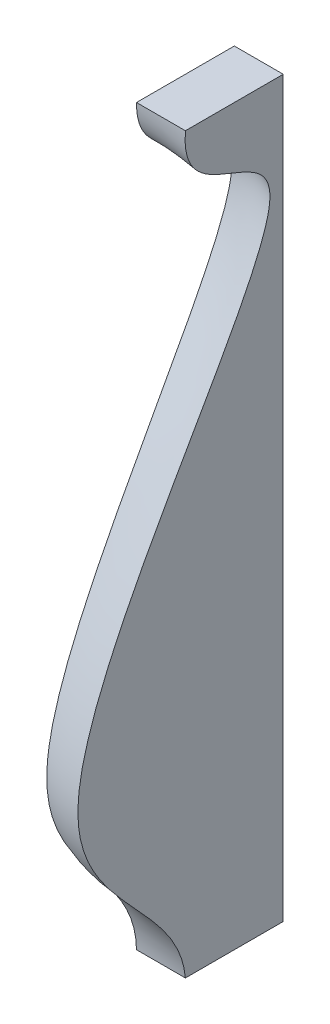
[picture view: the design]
ISO-10303-21;
HEADER;
FILE_DESCRIPTION(('STEP AP214'),'2;1');
FILE_NAME('part.step','',(''),(''),'','','');
FILE_SCHEMA(('AUTOMOTIVE_DESIGN { 1 0 10303 214 1 1 1 1 }'));
ENDSEC;
DATA;
#1=APPLICATION_CONTEXT('core data for automotive mechanical design processes');
#2=APPLICATION_PROTOCOL_DEFINITION('international standard','automotive_design',2000,#1);
#3=PRODUCT_CONTEXT('',#1,'mechanical');
#4=PRODUCT('Part','Part','',(#3));
#5=PRODUCT_RELATED_PRODUCT_CATEGORY('part','',(#4));
#6=PRODUCT_DEFINITION_FORMATION('','',#4);
#7=PRODUCT_DEFINITION_CONTEXT('part definition',#1,'design');
#8=PRODUCT_DEFINITION('design','',#6,#7);
#9=PRODUCT_DEFINITION_SHAPE('','',#8);
#10=(LENGTH_UNIT() NAMED_UNIT(*) SI_UNIT(.MILLI.,.METRE.));
#11=(NAMED_UNIT(*) PLANE_ANGLE_UNIT() SI_UNIT($,.RADIAN.));
#12=(NAMED_UNIT(*) SI_UNIT($,.STERADIAN.) SOLID_ANGLE_UNIT());
#13=UNCERTAINTY_MEASURE_WITH_UNIT(LENGTH_MEASURE(1.E-05),#10,'distance_accuracy_value','');
#14=(GEOMETRIC_REPRESENTATION_CONTEXT(3) GLOBAL_UNCERTAINTY_ASSIGNED_CONTEXT((#13)) GLOBAL_UNIT_ASSIGNED_CONTEXT((#10,
#11,#12)) REPRESENTATION_CONTEXT('',''));
#15=CARTESIAN_POINT('',(0.,0.,0.));
#16=DIRECTION('',(0.,0.,1.));
#17=DIRECTION('',(1.,0.,0.));
#18=AXIS2_PLACEMENT_3D('',#15,#16,#17);
#19=CARTESIAN_POINT('',(-150.,375.,253.120113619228));
#20=DIRECTION('',(1.,0.,0.));
#21=DIRECTION('',(0.,0.,-1.));
#22=AXIS2_PLACEMENT_3D('',#19,#20,#21);
#23=PLANE('',#22);
#24=CARTESIAN_POINT('',(-150.,375.,100.));
#25=CARTESIAN_POINT('',(-150.,374.21653675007,100.066588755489));
#26=CARTESIAN_POINT('',(-150.,373.432207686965,100.123521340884));
#27=CARTESIAN_POINT('',(-150.,371.859019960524,100.216681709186));
#28=CARTESIAN_POINT('',(-150.,371.070156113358,100.252821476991));
#29=CARTESIAN_POINT('',(-150.,369.489544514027,100.302484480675));
#30=CARTESIAN_POINT('',(-150.,368.697794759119,100.315945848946));
#31=CARTESIAN_POINT('',(-150.,367.113088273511,100.318286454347));
#32=CARTESIAN_POINT('',(-150.,366.320131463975,100.307129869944));
#33=CARTESIAN_POINT('',(-150.,364.734681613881,100.25826156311));
#34=CARTESIAN_POINT('',(-150.,363.942188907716,100.220538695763));
#35=CARTESIAN_POINT('',(-150.,362.348389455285,100.115833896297));
#36=CARTESIAN_POINT('',(-150.,361.54710777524,100.048464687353));
#37=CARTESIAN_POINT('',(-150.,359.94848717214,99.8823244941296));
#38=CARTESIAN_POINT('',(-150.,359.151145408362,99.7835810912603));
#39=CARTESIAN_POINT('',(-150.,357.56214923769,99.5526394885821));
#40=CARTESIAN_POINT('',(-150.,356.770489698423,99.420476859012));
#41=CARTESIAN_POINT('',(-150.,355.194608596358,99.1206798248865));
#42=CARTESIAN_POINT('',(-150.,354.410381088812,98.9530768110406));
#43=CARTESIAN_POINT('',(-150.,352.851074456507,98.5804242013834));
#44=CARTESIAN_POINT('',(-150.,352.075992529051,98.3753864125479));
#45=CARTESIAN_POINT('',(-150.,350.724720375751,97.9808842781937));
#46=CARTESIAN_POINT('',(-150.,350.146075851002,97.7997941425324));
#47=CARTESIAN_POINT('',(-150.,348.996367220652,97.4145841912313));
#48=CARTESIAN_POINT('',(-150.,348.425304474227,97.2104603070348));
#49=CARTESIAN_POINT('',(-150.,347.292094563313,96.7787729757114));
#50=CARTESIAN_POINT('',(-150.,346.729947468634,96.5512093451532));
#51=CARTESIAN_POINT('',(-150.,345.61582654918,96.0723947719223));
#52=CARTESIAN_POINT('',(-150.,345.063852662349,95.8211439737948));
#53=CARTESIAN_POINT('',(-150.,343.974984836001,95.2966788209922));
#54=CARTESIAN_POINT('',(-150.,343.438014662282,95.0236228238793));
#55=CARTESIAN_POINT('',(-150.,342.376502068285,94.4542750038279));
#56=CARTESIAN_POINT('',(-150.,341.851960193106,94.1579821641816));
#57=CARTESIAN_POINT('',(-150.,340.816444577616,93.542594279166));
#58=CARTESIAN_POINT('',(-150.,340.30547047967,93.2234998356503));
#59=CARTESIAN_POINT('',(-150.,339.29809746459,92.5631666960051));
#60=CARTESIAN_POINT('',(-150.,338.801697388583,92.2219297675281));
#61=CARTESIAN_POINT('',(-150.,337.824157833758,91.5180631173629));
#62=CARTESIAN_POINT('',(-150.,337.343021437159,91.1554291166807));
#63=CARTESIAN_POINT('',(-150.,336.396709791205,90.4098173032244));
#64=CARTESIAN_POINT('',(-150.,335.931536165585,90.0268374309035));
#65=CARTESIAN_POINT('',(-150.,335.017676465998,89.2417622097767));
#66=CARTESIAN_POINT('',(-150.,334.568989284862,88.8396681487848));
#67=CARTESIAN_POINT('',(-150.,333.688265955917,88.0175748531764));
#68=CARTESIAN_POINT('',(-150.,333.25623143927,87.5975738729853));
#69=CARTESIAN_POINT('',(-150.,332.407491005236,86.7396163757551));
#70=CARTESIAN_POINT('',(-150.,331.990840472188,86.3016050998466));
#71=CARTESIAN_POINT('',(-150.,331.174201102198,85.4102924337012));
#72=CARTESIAN_POINT('',(-150.,330.774213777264,84.9569896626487));
#73=CARTESIAN_POINT('',(-150.,329.598888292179,83.576292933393));
#74=CARTESIAN_POINT('',(-150.,328.848012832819,82.6279335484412));
#75=CARTESIAN_POINT('',(-150.,327.467283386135,80.7666367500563));
#76=CARTESIAN_POINT('',(-150.,326.832556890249,79.8572749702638));
#77=CARTESIAN_POINT('',(-150.,325.610003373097,78.0077037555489));
#78=CARTESIAN_POINT('',(-150.,325.022174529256,77.0674955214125));
#79=CARTESIAN_POINT('',(-150.,323.889712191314,75.1649302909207));
#80=CARTESIAN_POINT('',(-150.,323.34496828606,74.2026386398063));
#81=CARTESIAN_POINT('',(-150.,322.291476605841,72.2586952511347));
#82=CARTESIAN_POINT('',(-150.,321.782727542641,71.2770442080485));
#83=CARTESIAN_POINT('',(-150.,320.63552275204,68.9777823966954));
#84=CARTESIAN_POINT('',(-150.,320.008519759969,67.6544774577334));
#85=CARTESIAN_POINT('',(-150.,318.794868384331,64.9892511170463));
#86=CARTESIAN_POINT('',(-150.,318.208231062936,63.6473247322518));
#87=CARTESIAN_POINT('',(-150.,317.062805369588,60.9513675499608));
#88=CARTESIAN_POINT('',(-150.,316.504023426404,59.597334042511));
#89=CARTESIAN_POINT('',(-150.,315.397407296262,56.8714769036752));
#90=CARTESIAN_POINT('',(-150.,314.849706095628,55.4995997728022));
#91=CARTESIAN_POINT('',(-150.,313.757540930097,52.7549957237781));
#92=CARTESIAN_POINT('',(-150.,313.213076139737,51.3822691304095));
#93=CARTESIAN_POINT('',(-150.,312.114075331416,48.6410881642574));
#94=CARTESIAN_POINT('',(-150.,311.559541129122,47.2726330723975));
#95=CARTESIAN_POINT('',(-150.,310.560688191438,44.8696426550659));
#96=CARTESIAN_POINT('',(-150.,310.121475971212,43.8329980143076));
#97=CARTESIAN_POINT('',(-150.,309.221955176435,41.7687426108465));
#98=CARTESIAN_POINT('',(-150.,308.761644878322,40.7411325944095));
#99=CARTESIAN_POINT('',(-150.,307.812238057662,38.6985133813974));
#100=CARTESIAN_POINT('',(-150.,307.323125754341,37.6835114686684));
#101=CARTESIAN_POINT('',(-150.,306.307310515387,35.6701753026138));
#102=CARTESIAN_POINT('',(-150.,305.780544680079,34.6718725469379));
#103=CARTESIAN_POINT('',(-150.,304.689245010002,32.7148472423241));
#104=CARTESIAN_POINT('',(-150.,304.125369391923,31.7557607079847));
#105=CARTESIAN_POINT('',(-150.,302.94448102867,29.8710201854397));
#106=CARTESIAN_POINT('',(-150.,302.327483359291,28.9453568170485));
#107=CARTESIAN_POINT('',(-150.,301.032771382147,27.1401042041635));
#108=CARTESIAN_POINT('',(-150.,300.355198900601,26.2604146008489));
#109=CARTESIAN_POINT('',(-150.,299.287718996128,24.9849865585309));
#110=CARTESIAN_POINT('',(-150.,298.923665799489,24.5674930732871));
#111=CARTESIAN_POINT('',(-150.,298.177696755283,23.7488161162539));
#112=CARTESIAN_POINT('',(-150.,297.795783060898,23.3476306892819));
#113=CARTESIAN_POINT('',(-150.,296.968191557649,22.5180017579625));
#114=CARTESIAN_POINT('',(-150.,296.52025836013,22.0918005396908));
#115=CARTESIAN_POINT('',(-150.,295.60124663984,21.2648995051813));
#116=CARTESIAN_POINT('',(-150.,295.13016385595,20.864204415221));
#117=CARTESIAN_POINT('',(-150.,294.165268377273,20.0911470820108));
#118=CARTESIAN_POINT('',(-150.,293.671456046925,19.7187843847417));
#119=CARTESIAN_POINT('',(-150.,292.661853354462,19.0047717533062));
#120=CARTESIAN_POINT('',(-150.,292.146056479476,18.6631310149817));
#121=CARTESIAN_POINT('',(-150.,291.094083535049,18.0127470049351));
#122=CARTESIAN_POINT('',(-150.,290.557906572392,17.7040051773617));
#123=CARTESIAN_POINT('',(-150.,289.467181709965,17.120952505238));
#124=CARTESIAN_POINT('',(-150.,288.912635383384,16.8466387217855));
#125=CARTESIAN_POINT('',(-150.,287.928683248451,16.3976627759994));
#126=CARTESIAN_POINT('',(-150.,287.502783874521,16.2152650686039));
#127=CARTESIAN_POINT('',(-150.,286.642984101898,15.8702954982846));
#128=CARTESIAN_POINT('',(-150.,286.209083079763,15.7077251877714));
#129=CARTESIAN_POINT('',(-150.,285.33444189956,15.4023310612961));
#130=CARTESIAN_POINT('',(-150.,284.893702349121,15.2595055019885));
#131=CARTESIAN_POINT('',(-150.,284.006359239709,14.9932546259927));
#132=CARTESIAN_POINT('',(-150.,283.559755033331,14.8698314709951));
#133=CARTESIAN_POINT('',(-150.,282.661325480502,14.6418217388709));
#134=CARTESIAN_POINT('',(-150.,282.209495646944,14.5372528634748));
#135=CARTESIAN_POINT('',(-150.,281.301960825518,14.3464721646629));
#136=CARTESIAN_POINT('',(-150.,280.846255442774,14.2602622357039));
#137=CARTESIAN_POINT('',(-150.,279.474645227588,14.028127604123));
#138=CARTESIAN_POINT('',(-150.,278.554159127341,13.9086762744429));
#139=CARTESIAN_POINT('',(-150.,276.697492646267,13.7330760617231));
#140=CARTESIAN_POINT('',(-150.,275.7612498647,13.6776205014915));
#141=CARTESIAN_POINT('',(-150.,273.886746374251,13.625270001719));
#142=CARTESIAN_POINT('',(-150.,272.948484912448,13.6284031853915));
#143=CARTESIAN_POINT('',(-150.,271.542442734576,13.6720229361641));
#144=CARTESIAN_POINT('',(-150.,271.073942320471,13.6930533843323));
#145=CARTESIAN_POINT('',(-150.,270.13763650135,13.7473078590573));
#146=CARTESIAN_POINT('',(-150.,269.669831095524,13.7805318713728));
#147=CARTESIAN_POINT('',(-150.,268.733577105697,13.8585469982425));
#148=CARTESIAN_POINT('',(-150.,268.265131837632,13.9033774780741));
#149=CARTESIAN_POINT('',(-150.,267.329408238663,14.0038645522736));
#150=CARTESIAN_POINT('',(-150.,266.862129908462,14.0595211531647));
#151=CARTESIAN_POINT('',(-150.,265.929013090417,14.1808012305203));
#152=CARTESIAN_POINT('',(-150.,265.463174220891,14.2464217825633));
#153=CARTESIAN_POINT('',(-150.,264.532883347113,14.3867891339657));
#154=CARTESIAN_POINT('',(-150.,264.06843134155,14.4615359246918));
#155=CARTESIAN_POINT('',(-150.,262.677292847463,14.6983326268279));
#156=CARTESIAN_POINT('',(-150.,261.752728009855,14.8729516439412));
#157=CARTESIAN_POINT('',(-150.,260.000822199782,15.23198624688));
#158=CARTESIAN_POINT('',(-150.,259.172922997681,15.4137178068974));
#159=CARTESIAN_POINT('',(-150.,257.521795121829,15.7974210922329));
#160=CARTESIAN_POINT('',(-150.,256.698566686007,15.9993938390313));
#161=CARTESIAN_POINT('',(-150.,255.056365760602,16.421225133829));
#162=CARTESIAN_POINT('',(-150.,254.237395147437,16.6410909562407));
#163=CARTESIAN_POINT('',(-150.,252.60388138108,17.096608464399));
#164=CARTESIAN_POINT('',(-150.,251.789338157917,17.3322598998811));
#165=CARTESIAN_POINT('',(-150.,250.16346493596,17.8179445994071));
#166=CARTESIAN_POINT('',(-150.,249.352140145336,18.0679952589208));
#167=CARTESIAN_POINT('',(-150.,247.733506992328,18.5807609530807));
#168=CARTESIAN_POINT('',(-150.,246.926198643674,18.8434760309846));
#169=CARTESIAN_POINT('',(-150.,245.314470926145,19.3806316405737));
#170=CARTESIAN_POINT('',(-150.,244.510055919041,19.6550852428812));
#171=CARTESIAN_POINT('',(-150.,242.904837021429,20.2143688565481));
#172=CARTESIAN_POINT('',(-150.,242.104033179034,20.499199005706));
#173=CARTESIAN_POINT('',(-150.,239.705806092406,21.3681600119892));
#174=CARTESIAN_POINT('',(-150.,238.113500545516,21.9664479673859));
#175=CARTESIAN_POINT('',(-150.,234.941514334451,23.1944367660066));
#176=CARTESIAN_POINT('',(-150.,233.36183097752,23.8241306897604));
#177=CARTESIAN_POINT('',(-150.,230.203288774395,25.1144376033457));
#178=CARTESIAN_POINT('',(-150.,228.624500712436,25.7752235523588));
#179=CARTESIAN_POINT('',(-150.,225.478553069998,27.1193081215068));
#180=CARTESIAN_POINT('',(-150.,223.911382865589,27.8025819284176));
#181=CARTESIAN_POINT('',(-150.,220.787111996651,29.1886679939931));
#182=CARTESIAN_POINT('',(-150.,219.230004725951,29.8914653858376));
#183=CARTESIAN_POINT('',(-150.,216.124550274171,31.3141680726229));
#184=CARTESIAN_POINT('',(-150.,214.576199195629,32.034064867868));
#185=CARTESIAN_POINT('',(-150.,212.259309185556,33.1252859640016));
#186=CARTESIAN_POINT('',(-150.,211.488059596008,33.490870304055));
#187=CARTESIAN_POINT('',(-150.,209.947273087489,34.2256351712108));
#188=CARTESIAN_POINT('',(-150.,209.177736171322,34.5948157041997));
#189=CARTESIAN_POINT('',(-150.,207.640376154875,35.3365139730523));
#190=CARTESIAN_POINT('',(-150.,206.872552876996,35.7090313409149));
#191=CARTESIAN_POINT('',(-150.,205.338463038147,36.457242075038));
#192=CARTESIAN_POINT('',(-150.,204.572196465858,36.8329354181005));
#193=CARTESIAN_POINT('',(-150.,201.997162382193,38.1016951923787));
#194=CARTESIAN_POINT('',(-150.,200.191771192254,39.001622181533));
#195=CARTESIAN_POINT('',(-150.,196.588308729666,40.8160282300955));
#196=CARTESIAN_POINT('',(-150.,194.790237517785,41.7305074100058));
#197=CARTESIAN_POINT('',(-150.,191.200524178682,43.5722494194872));
#198=CARTESIAN_POINT('',(-150.,189.408882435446,44.4995129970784));
#199=CARTESIAN_POINT('',(-150.,185.831432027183,46.365206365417));
#200=CARTESIAN_POINT('',(-150.,184.045623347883,47.3036361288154));
#201=CARTESIAN_POINT('',(-150.,180.478979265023,49.1904276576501));
#202=CARTESIAN_POINT('',(-150.,178.698144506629,50.1387906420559));
#203=CARTESIAN_POINT('',(-150.,175.141101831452,52.0441575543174));
#204=CARTESIAN_POINT('',(-150.,173.364893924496,53.0011615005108));
#205=CARTESIAN_POINT('',(-150.,168.042124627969,55.8836989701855));
#206=CARTESIAN_POINT('',(-150.,164.501717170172,57.8205992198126));
#207=CARTESIAN_POINT('',(-150.,157.433752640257,61.7176161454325));
#208=CARTESIAN_POINT('',(-150.,153.90619550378,63.6777327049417));
#209=CARTESIAN_POINT('',(-150.,146.856580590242,67.6178956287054));
#210=CARTESIAN_POINT('',(-150.,143.334534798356,69.5979634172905));
#211=CARTESIAN_POINT('',(-150.,136.297984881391,73.5706523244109));
#212=CARTESIAN_POINT('',(-150.,132.783480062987,75.563272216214));
#213=CARTESIAN_POINT('',(-150.,125.759562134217,79.5569953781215));
#214=CARTESIAN_POINT('',(-150.,122.250148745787,81.5580981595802));
#215=CARTESIAN_POINT('',(-150.,115.234233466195,85.5651869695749));
#216=CARTESIAN_POINT('',(-150.,111.727731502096,87.5711728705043));
#217=CARTESIAN_POINT('',(-150.,104.715655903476,91.5847729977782));
#218=CARTESIAN_POINT('',(-150.,101.210082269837,93.5923872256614));
#219=CARTESIAN_POINT('',(-150.,93.3492371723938,98.0920857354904));
#220=CARTESIAN_POINT('',(-150.,88.9937416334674,100.583778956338));
#221=CARTESIAN_POINT('',(-150.,80.2782170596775,105.55946742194));
#222=CARTESIAN_POINT('',(-150.,75.9181879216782,108.043462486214));
#223=CARTESIAN_POINT('',(-150.,67.1906031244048,112.998412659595));
#224=CARTESIAN_POINT('',(-150.,62.8230473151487,115.469367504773));
#225=CARTESIAN_POINT('',(-150.,54.0774394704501,120.392937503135));
#226=CARTESIAN_POINT('',(-150.,49.6993871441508,122.845552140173));
#227=CARTESIAN_POINT('',(-150.,40.9325384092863,127.725490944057));
#228=CARTESIAN_POINT('',(-150.,36.5437497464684,130.152829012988));
#229=CARTESIAN_POINT('',(-150.,27.7499512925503,134.977900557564));
#230=CARTESIAN_POINT('',(-150.,23.3449416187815,137.375634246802));
#231=CARTESIAN_POINT('',(-150.,14.5157681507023,142.135202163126));
#232=CARTESIAN_POINT('',(-150.,10.09160508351,144.497037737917));
#233=CARTESIAN_POINT('',(-150.,1.2208532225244,149.177958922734));
#234=CARTESIAN_POINT('',(-150.,-3.2257348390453,151.497045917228));
#235=CARTESIAN_POINT('',(-150.,-8.95319422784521,154.443019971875));
#236=CARTESIAN_POINT('',(-150.,-10.2221397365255,155.093132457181));
#237=CARTESIAN_POINT('',(-150.,-12.7622193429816,156.389071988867));
#238=CARTESIAN_POINT('',(-150.,-14.0333534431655,157.034899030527));
#239=CARTESIAN_POINT('',(-150.,-17.8503370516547,158.965736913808));
#240=CARTESIAN_POINT('',(-150.,-20.3995969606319,160.244016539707));
#241=CARTESIAN_POINT('',(-150.,-25.508054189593,162.780943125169));
#242=CARTESIAN_POINT('',(-150.,-28.0672520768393,164.039588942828));
#243=CARTESIAN_POINT('',(-150.,-33.1963438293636,166.535320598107));
#244=CARTESIAN_POINT('',(-150.,-35.7662383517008,167.772405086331));
#245=CARTESIAN_POINT('',(-150.,-40.9175691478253,170.222901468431));
#246=CARTESIAN_POINT('',(-150.,-43.4990063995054,171.436311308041));
#247=CARTESIAN_POINT('',(-150.,-48.6914154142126,173.845031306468));
#248=CARTESIAN_POINT('',(-150.,-51.3024690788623,175.040165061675));
#249=CARTESIAN_POINT('',(-150.,-56.5377935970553,177.401192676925));
#250=CARTESIAN_POINT('',(-150.,-59.1620645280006,178.567086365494));
#251=CARTESIAN_POINT('',(-150.,-64.424522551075,180.866443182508));
#252=CARTESIAN_POINT('',(-150.,-67.0627084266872,181.999909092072));
#253=CARTESIAN_POINT('',(-150.,-72.3538513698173,184.230851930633));
#254=CARTESIAN_POINT('',(-150.,-75.0068063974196,185.328333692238));
#255=CARTESIAN_POINT('',(-150.,-80.3285429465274,187.483311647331));
#256=CARTESIAN_POINT('',(-150.,-82.9973224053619,188.540812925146));
#257=CARTESIAN_POINT('',(-150.,-87.9347409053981,190.44993295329));
#258=CARTESIAN_POINT('',(-150.,-90.2009055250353,191.307948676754));
#259=CARTESIAN_POINT('',(-150.,-94.7461611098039,192.989041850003));
#260=CARTESIAN_POINT('',(-150.,-97.0252519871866,193.81211953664));
#261=CARTESIAN_POINT('',(-150.,-101.597317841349,195.419762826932));
#262=CARTESIAN_POINT('',(-150.,-103.890294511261,196.204323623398));
#263=CARTESIAN_POINT('',(-150.,-108.491268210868,197.730841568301));
#264=CARTESIAN_POINT('',(-150.,-110.799270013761,198.472784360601));
#265=CARTESIAN_POINT('',(-150.,-115.431641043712,199.90933696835));
#266=CARTESIAN_POINT('',(-150.,-117.756019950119,200.603915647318));
#267=CARTESIAN_POINT('',(-150.,-122.422768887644,201.940218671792));
#268=CARTESIAN_POINT('',(-150.,-124.765156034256,202.581883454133));
#269=CARTESIAN_POINT('',(-150.,-129.442344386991,203.798660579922));
#270=CARTESIAN_POINT('',(-150.,-131.776989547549,204.374371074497));
#271=CARTESIAN_POINT('',(-150.,-136.462638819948,205.458979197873));
#272=CARTESIAN_POINT('',(-150.,-138.813647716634,205.967856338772));
#273=CARTESIAN_POINT('',(-150.,-142.350836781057,206.673832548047));
#274=CARTESIAN_POINT('',(-150.,-143.531346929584,206.899546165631));
#275=CARTESIAN_POINT('',(-150.,-145.896096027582,207.330611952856));
#276=CARTESIAN_POINT('',(-150.,-147.080334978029,207.535964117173));
#277=CARTESIAN_POINT('',(-150.,-149.451071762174,207.924670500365));
#278=CARTESIAN_POINT('',(-150.,-150.63756561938,208.108048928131));
#279=CARTESIAN_POINT('',(-150.,-153.013915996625,208.451520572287));
#280=CARTESIAN_POINT('',(-150.,-154.203772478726,208.61161405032));
#281=CARTESIAN_POINT('',(-150.,-156.585258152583,208.906662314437));
#282=CARTESIAN_POINT('',(-150.,-157.776883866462,209.041645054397));
#283=CARTESIAN_POINT('',(-150.,-160.162880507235,209.284848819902));
#284=CARTESIAN_POINT('',(-150.,-161.357251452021,209.393069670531));
#285=CARTESIAN_POINT('',(-150.,-163.747850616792,209.580721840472));
#286=CARTESIAN_POINT('',(-150.,-164.944078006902,209.660163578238));
#287=CARTESIAN_POINT('',(-150.,-166.739622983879,209.756095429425));
#288=CARTESIAN_POINT('',(-150.,-167.338335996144,209.784200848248));
#289=CARTESIAN_POINT('',(-150.,-168.536080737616,209.832471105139));
#290=CARTESIAN_POINT('',(-150.,-169.135112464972,209.852635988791));
#291=CARTESIAN_POINT('',(-150.,-170.49711131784,209.889329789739));
#292=CARTESIAN_POINT('',(-150.,-171.260147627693,209.903359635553));
#293=CARTESIAN_POINT('',(-150.,-172.786330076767,209.918128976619));
#294=CARTESIAN_POINT('',(-150.,-173.54947621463,209.91886862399));
#295=CARTESIAN_POINT('',(-150.,-175.8391890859,209.900805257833));
#296=CARTESIAN_POINT('',(-150.,-177.365653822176,209.861709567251));
#297=CARTESIAN_POINT('',(-150.,-180.416226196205,209.727784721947));
#298=CARTESIAN_POINT('',(-150.,-181.940333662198,209.632951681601));
#299=CARTESIAN_POINT('',(-150.,-184.983915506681,209.386261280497));
#300=CARTESIAN_POINT('',(-150.,-186.503389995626,209.234405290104));
#301=CARTESIAN_POINT('',(-150.,-189.535394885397,208.872761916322));
#302=CARTESIAN_POINT('',(-150.,-191.047925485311,208.662976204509));
#303=CARTESIAN_POINT('',(-150.,-194.061898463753,208.185283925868));
#304=CARTESIAN_POINT('',(-150.,-195.563352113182,207.917448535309));
#305=CARTESIAN_POINT('',(-150.,-198.554832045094,207.32347300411));
#306=CARTESIAN_POINT('',(-150.,-200.044857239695,206.997327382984));
#307=CARTESIAN_POINT('',(-150.,-203.011110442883,206.287224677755));
#308=CARTESIAN_POINT('',(-150.,-204.487338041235,205.903265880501));
#309=CARTESIAN_POINT('',(-150.,-207.423765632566,205.078539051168));
#310=CARTESIAN_POINT('',(-150.,-208.883966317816,204.637773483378));
#311=CARTESIAN_POINT('',(-150.,-211.786218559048,203.700967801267));
#312=CARTESIAN_POINT('',(-150.,-213.228273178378,203.204937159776));
#313=CARTESIAN_POINT('',(-150.,-216.438013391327,202.033428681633));
#314=CARTESIAN_POINT('',(-150.,-218.200442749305,201.343510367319));
#315=CARTESIAN_POINT('',(-150.,-221.692689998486,199.88575453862));
#316=CARTESIAN_POINT('',(-150.,-223.422507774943,199.117916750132));
#317=CARTESIAN_POINT('',(-150.,-226.848126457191,197.509339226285));
#318=CARTESIAN_POINT('',(-150.,-228.543922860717,196.668589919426));
#319=CARTESIAN_POINT('',(-150.,-231.900382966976,194.91992859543));
#320=CARTESIAN_POINT('',(-150.,-233.561047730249,194.012018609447));
#321=CARTESIAN_POINT('',(-150.,-236.852124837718,192.132166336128));
#322=CARTESIAN_POINT('',(-150.,-238.48243405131,191.160043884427));
#323=CARTESIAN_POINT('',(-150.,-241.708323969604,189.160358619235));
#324=CARTESIAN_POINT('',(-150.,-243.303909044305,188.132802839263));
#325=CARTESIAN_POINT('',(-150.,-246.461838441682,186.02827140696));
#326=CARTESIAN_POINT('',(-150.,-248.024186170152,184.951300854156));
#327=CARTESIAN_POINT('',(-150.,-251.117230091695,182.754138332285));
#328=CARTESIAN_POINT('',(-150.,-252.647937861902,181.633962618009));
#329=CARTESIAN_POINT('',(-150.,-256.207052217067,178.960329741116));
#330=CARTESIAN_POINT('',(-150.,-258.223836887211,177.391410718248));
#331=CARTESIAN_POINT('',(-150.,-262.212337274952,174.198129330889));
#332=CARTESIAN_POINT('',(-150.,-264.18405922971,172.57377471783));
#333=CARTESIAN_POINT('',(-150.,-268.091832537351,169.280840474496));
#334=CARTESIAN_POINT('',(-150.,-270.027864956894,167.612238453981));
#335=CARTESIAN_POINT('',(-150.,-273.873475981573,164.241911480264));
#336=CARTESIAN_POINT('',(-150.,-275.783032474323,162.540161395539));
#337=CARTESIAN_POINT('',(-150.,-279.584914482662,159.114625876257));
#338=CARTESIAN_POINT('',(-150.,-281.47722534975,157.390824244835));
#339=CARTESIAN_POINT('',(-150.,-285.253952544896,153.932412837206));
#340=CARTESIAN_POINT('',(-150.,-287.138363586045,152.197797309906));
#341=CARTESIAN_POINT('',(-150.,-290.906536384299,148.731418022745));
#342=CARTESIAN_POINT('',(-150.,-292.79029708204,146.999653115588));
#343=CARTESIAN_POINT('',(-150.,-296.568819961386,143.549283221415));
#344=CARTESIAN_POINT('',(-150.,-298.463578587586,141.830674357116));
#345=CARTESIAN_POINT('',(-150.,-302.273923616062,138.419642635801));
#346=CARTESIAN_POINT('',(-150.,-304.189492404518,136.727200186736));
#347=CARTESIAN_POINT('',(-150.,-308.051925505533,133.382245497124));
#348=CARTESIAN_POINT('',(-150.,-309.998755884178,131.729694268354));
#349=CARTESIAN_POINT('',(-150.,-313.934930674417,128.479192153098));
#350=CARTESIAN_POINT('',(-150.,-315.924238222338,126.881196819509));
#351=CARTESIAN_POINT('',(-150.,-319.957681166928,123.755482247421));
#352=CARTESIAN_POINT('',(-150.,-322.001815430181,122.227761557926));
#353=CARTESIAN_POINT('',(-150.,-325.291926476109,119.878375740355));
#354=CARTESIAN_POINT('',(-150.,-326.516731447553,119.027032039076));
#355=CARTESIAN_POINT('',(-150.,-328.990551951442,117.359163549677));
#356=CARTESIAN_POINT('',(-150.,-330.239576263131,116.54265174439));
#357=CARTESIAN_POINT('',(-150.,-332.763008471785,114.949283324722));
#358=CARTESIAN_POINT('',(-150.,-334.037420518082,114.172433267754));
#359=CARTESIAN_POINT('',(-150.,-336.612818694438,112.663207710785));
#360=CARTESIAN_POINT('',(-150.,-337.913811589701,111.930843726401));
#361=CARTESIAN_POINT('',(-150.,-340.536252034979,110.519286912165));
#362=CARTESIAN_POINT('',(-150.,-341.857569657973,109.839853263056));
#363=CARTESIAN_POINT('',(-150.,-344.526809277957,108.535259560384));
#364=CARTESIAN_POINT('',(-150.,-345.87473138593,107.910099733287));
#365=CARTESIAN_POINT('',(-150.,-348.596027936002,106.719206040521));
#366=CARTESIAN_POINT('',(-150.,-349.969392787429,106.153450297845));
#367=CARTESIAN_POINT('',(-150.,-352.740265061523,105.0859307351));
#368=CARTESIAN_POINT('',(-150.,-354.137762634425,104.584141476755));
#369=CARTESIAN_POINT('',(-150.,-356.331575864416,103.855571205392));
#370=CARTESIAN_POINT('',(-150.,-357.120182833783,103.605377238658));
#371=CARTESIAN_POINT('',(-150.,-358.703909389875,103.126693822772));
#372=CARTESIAN_POINT('',(-150.,-359.499028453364,102.898202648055));
#373=CARTESIAN_POINT('',(-150.,-361.095253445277,102.463475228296));
#374=CARTESIAN_POINT('',(-150.,-361.896358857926,102.257237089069));
#375=CARTESIAN_POINT('',(-150.,-363.504028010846,101.867457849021));
#376=CARTESIAN_POINT('',(-150.,-364.310591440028,101.68391546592));
#377=CARTESIAN_POINT('',(-150.,-365.934639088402,101.338596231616));
#378=CARTESIAN_POINT('',(-150.,-366.752159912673,101.176991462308));
#379=CARTESIAN_POINT('',(-150.,-368.391575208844,100.877425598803));
#380=CARTESIAN_POINT('',(-150.,-369.213469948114,100.739465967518));
#381=CARTESIAN_POINT('',(-150.,-370.861035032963,100.487345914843));
#382=CARTESIAN_POINT('',(-150.,-371.686705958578,100.373189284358));
#383=CARTESIAN_POINT('',(-150.,-373.341208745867,100.168702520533));
#384=CARTESIAN_POINT('',(-150.,-374.170041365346,100.078378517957));
#385=CARTESIAN_POINT('',(-150.,-375.,100.));
#386=B_SPLINE_CURVE_WITH_KNOTS('',3,(#24,#25,#26,#27,#28,#29,#30,#31,#32,#33,#34,#35,#36,#37,
#38,#39,#40,#41,#42,#43,#44,#45,#46,#47,#48,#49,#50,#51,#52,#53,#54,#55,#56,#57,#58,#59,#60,#61,
#62,#63,#64,#65,#66,#67,#68,#69,#70,#71,#72,#73,#74,#75,#76,#77,#78,#79,#80,#81,#82,#83,#84,#85,
#86,#87,#88,#89,#90,#91,#92,#93,#94,#95,#96,#97,#98,#99,#100,#101,#102,#103,#104,#105,#106,#107,
#108,#109,#110,#111,#112,#113,#114,#115,#116,#117,#118,#119,#120,#121,#122,#123,#124,#125,#126,
#127,#128,#129,#130,#131,#132,#133,#134,#135,#136,#137,#138,#139,#140,#141,#142,#143,#144,#145,
#146,#147,#148,#149,#150,#151,#152,#153,#154,#155,#156,#157,#158,#159,#160,#161,#162,#163,#164,
#165,#166,#167,#168,#169,#170,#171,#172,#173,#174,#175,#176,#177,#178,#179,#180,#181,#182,#183,
#184,#185,#186,#187,#188,#189,#190,#191,#192,#193,#194,#195,#196,#197,#198,#199,#200,#201,#202,
#203,#204,#205,#206,#207,#208,#209,#210,#211,#212,#213,#214,#215,#216,#217,#218,#219,#220,#221,
#222,#223,#224,#225,#226,#227,#228,#229,#230,#231,#232,#233,#234,#235,#236,#237,#238,#239,#240,
#241,#242,#243,#244,#245,#246,#247,#248,#249,#250,#251,#252,#253,#254,#255,#256,#257,#258,#259,
#260,#261,#262,#263,#264,#265,#266,#267,#268,#269,#270,#271,#272,#273,#274,#275,#276,#277,#278,
#279,#280,#281,#282,#283,#284,#285,#286,#287,#288,#289,#290,#291,#292,#293,#294,#295,#296,#297,
#298,#299,#300,#301,#302,#303,#304,#305,#306,#307,#308,#309,#310,#311,#312,#313,#314,#315,#316,
#317,#318,#319,#320,#321,#322,#323,#324,#325,#326,#327,#328,#329,#330,#331,#332,#333,#334,#335,
#336,#337,#338,#339,#340,#341,#342,#343,#344,#345,#346,#347,#348,#349,#350,#351,#352,#353,#354,
#355,#356,#357,#358,#359,#360,#361,#362,#363,#364,#365,#366,#367,#368,#369,#370,#371,#372,#373,
#374,#375,#376,#377,#378,#379,#380,#381,#382,#383,#384,#385),.UNSPECIFIED.,.F.,.F.,(4,2,2,2,2,2,
2,2,2,2,2,2,2,2,2,2,2,2,2,2,2,2,2,2,2,2,2,2,2,2,2,2,2,2,2,2,2,2,2,2,2,2,2,2,2,2,2,2,2,2,2,2,2,2,
2,2,2,2,2,2,2,2,2,2,2,2,2,2,2,2,2,2,2,2,2,2,2,2,2,2,2,2,2,2,2,2,2,2,2,2,2,2,2,2,2,2,2,2,2,2,2,2,
2,2,2,2,2,2,2,2,2,2,2,2,2,2,2,2,2,2,2,2,2,2,2,2,2,2,2,2,2,2,2,2,2,2,2,2,2,2,2,2,2,2,2,2,2,2,2,2,
2,2,2,2,2,2,2,2,2,2,2,2,2,2,2,2,2,2,2,2,2,2,2,2,2,2,2,2,2,2,4),(0.,2.35887092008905,
4.72765473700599,7.10289029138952,9.48158432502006,11.8612768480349,14.273023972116,
16.6826567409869,19.0897354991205,21.4946910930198,23.8988894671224,25.7174034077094,
27.536239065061,29.3550889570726,31.1739277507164,32.980585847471,34.7873230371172,
36.5940125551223,38.400558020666,40.2074659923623,42.0145572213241,43.8215268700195,
45.6286730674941,47.441792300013,49.2550756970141,52.8809000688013,56.2063043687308,
59.5315793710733,62.848036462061,66.1643747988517,70.5563874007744,74.9495988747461,
79.3438196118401,83.7752962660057,88.2055894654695,92.6350915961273,96.0124859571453,
99.3901567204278,102.769695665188,106.155018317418,109.491264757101,112.826567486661,
116.154256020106,117.815597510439,119.476739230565,121.330721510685,123.185046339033,
125.039341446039,126.894189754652,128.749119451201,130.603890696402,131.993359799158,
133.382937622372,134.772392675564,136.16200242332,137.55291011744,138.943961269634,
141.725794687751,144.537491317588,147.350537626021,148.757329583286,150.164119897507,
151.575745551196,152.987372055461,154.398585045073,155.809796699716,158.631930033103,
161.174498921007,163.717196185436,166.260932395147,168.804628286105,171.351464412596,
173.898309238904,176.44806777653,178.997860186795,184.100397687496,189.201815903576,
194.336077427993,199.464852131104,204.589823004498,209.71229759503,212.272817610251,
214.83334181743,217.393587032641,219.95381356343,226.005484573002,232.057205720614,
238.109282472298,244.161344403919,250.21415793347,256.266984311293,268.373654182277,
280.480263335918,292.601664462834,304.721898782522,316.841444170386,328.960676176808,
341.079919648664,356.133484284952,371.187399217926,386.241617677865,401.296258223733,
416.34212771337,431.387888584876,446.43308319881,461.477789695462,465.755145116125,
470.032505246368,478.587802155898,487.143594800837,495.699920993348,504.256986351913,
512.871549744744,521.486163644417,530.100036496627,538.712747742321,547.324359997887,
554.593578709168,561.862748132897,569.132822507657,576.405331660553,583.682576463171,
590.967904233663,598.180813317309,605.395928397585,609.001466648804,612.607005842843,
616.208535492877,619.810024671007,623.407480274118,627.00495938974,630.601134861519,
632.399206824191,634.197268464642,636.486640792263,638.775986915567,643.35580833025,
647.935949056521,652.515979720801,657.09587824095,661.670192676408,666.244937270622,
670.819817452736,675.39449924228,679.96839810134,685.644325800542,691.320273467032,
696.996967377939,702.673489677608,708.366677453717,714.059144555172,719.75102551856,
725.440785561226,733.105017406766,740.768181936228,748.435301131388,756.108478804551,
763.787659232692,771.471347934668,779.147801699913,786.821898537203,794.489940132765,
802.150156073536,809.803974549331,817.457634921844,821.931995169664,826.408008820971,
830.884760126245,835.362665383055,839.818836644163,844.275026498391,848.729569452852,
853.182335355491,855.664101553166,858.145670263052,860.627027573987,863.10824462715,
865.607920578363,868.107751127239,870.607979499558,873.108850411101),.UNSPECIFIED.);
#387=CARTESIAN_POINT('',(-150.,375.,100.));
#388=VERTEX_POINT('',#387);
#389=CARTESIAN_POINT('',(-150.,-375.,100.));
#390=VERTEX_POINT('',#389);
#391=EDGE_CURVE('E88',#388,#390,#386,.T.);
#392=ORIENTED_EDGE('',*,*,#391,.T.);
#393=DIRECTION('',(0.,0.,-1.));
#394=VECTOR('',#393,1.);
#395=CARTESIAN_POINT('',(-150.,-375.,253.120113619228));
#396=LINE('',#395,#394);
#397=CARTESIAN_POINT('',(-150.,-375.,0.));
#398=VERTEX_POINT('',#397);
#399=EDGE_CURVE('E50',#390,#398,#396,.T.);
#400=ORIENTED_EDGE('',*,*,#399,.T.);
#401=DIRECTION('',(0.,-1.,0.));
#402=VECTOR('',#401,1.);
#403=CARTESIAN_POINT('',(-150.,375.,0.));
#404=LINE('',#403,#402);
#405=CARTESIAN_POINT('',(-150.,375.,0.));
#406=VERTEX_POINT('',#405);
#407=EDGE_CURVE('E87',#406,#398,#404,.T.);
#408=ORIENTED_EDGE('',*,*,#407,.F.);
#409=DIRECTION('',(0.,0.,-1.));
#410=VECTOR('',#409,1.);
#411=CARTESIAN_POINT('',(-150.,375.,253.120113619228));
#412=LINE('',#411,#410);
#413=EDGE_CURVE('E65',#388,#406,#412,.T.);
#414=ORIENTED_EDGE('',*,*,#413,.F.);
#415=EDGE_LOOP('',(#392,#400,#408,#414));
#416=FACE_BOUND('',#415,.T.);
#417=ADVANCED_FACE('F35',(#416),#23,.T.);
#418=CARTESIAN_POINT('',(0.,0.,0.));
#419=DIRECTION('',(0.,0.,-1.));
#420=DIRECTION('',(-1.,0.,0.));
#421=AXIS2_PLACEMENT_3D('',#418,#419,#420);
#422=PLANE('',#421);
#423=DIRECTION('',(1.,0.,0.));
#424=VECTOR('',#423,1.);
#425=CARTESIAN_POINT('',(-750.,-375.,0.));
#426=LINE('',#425,#424);
#427=CARTESIAN_POINT('',(-200.,-375.,0.));
#428=VERTEX_POINT('',#427);
#429=EDGE_CURVE('E79',#428,#398,#426,.T.);
#430=ORIENTED_EDGE('',*,*,#429,.F.);
#431=DIRECTION('',(0.,1.,0.));
#432=VECTOR('',#431,1.);
#433=CARTESIAN_POINT('',(-200.,375.,0.));
#434=LINE('',#433,#432);
#435=CARTESIAN_POINT('',(-200.,375.,0.));
#436=VERTEX_POINT('',#435);
#437=EDGE_CURVE('E157',#428,#436,#434,.T.);
#438=ORIENTED_EDGE('',*,*,#437,.T.);
#439=DIRECTION('',(-1.,0.,0.));
#440=VECTOR('',#439,1.);
#441=CARTESIAN_POINT('',(-750.,375.,0.));
#442=LINE('',#441,#440);
#443=EDGE_CURVE('E93',#406,#436,#442,.T.);
#444=ORIENTED_EDGE('',*,*,#443,.F.);
#445=ORIENTED_EDGE('',*,*,#407,.T.);
#446=EDGE_LOOP('',(#430,#438,#444,#445));
#447=FACE_BOUND('',#446,.T.);
#448=ADVANCED_FACE('F91',(#447),#422,.T.);
#449=CARTESIAN_POINT('',(750.,-375.,100.));
#450=CARTESIAN_POINT('',(750.,-302.078506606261,100.));
#451=CARTESIAN_POINT('',(750.,-224.483786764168,100.));
#452=CARTESIAN_POINT('',(750.,-61.5160152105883,100.));
#453=CARTESIAN_POINT('',(750.,39.4445673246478,100.));
#454=CARTESIAN_POINT('',(750.,211.849847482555,100.));
#455=CARTESIAN_POINT('',(750.,298.882075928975,100.));
#456=CARTESIAN_POINT('',(750.,375.,100.));
#457=CARTESIAN_POINT('',(669.085175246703,-375.,100.));
#458=CARTESIAN_POINT('',(669.085175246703,-302.078506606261,100.));
#459=CARTESIAN_POINT('',(669.085175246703,-234.282472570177,121.198481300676));
#460=CARTESIAN_POINT('',(669.085175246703,-62.2283080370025,120.288550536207));
#461=CARTESIAN_POINT('',(669.085175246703,68.0647781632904,82.7868169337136));
#462=CARTESIAN_POINT('',(669.085175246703,240.312514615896,73.0426687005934));
#463=CARTESIAN_POINT('',(669.085175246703,298.882075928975,100.));
#464=CARTESIAN_POINT('',(669.085175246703,375.,100.));
#465=CARTESIAN_POINT('',(500.445116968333,-375.,100.));
#466=CARTESIAN_POINT('',(517.991528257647,-284.627602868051,95.5040591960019));
#467=CARTESIAN_POINT('',(530.038001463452,-221.673003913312,150.719602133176));
#468=CARTESIAN_POINT('',(473.74510655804,-71.7416270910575,167.060530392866));
#469=CARTESIAN_POINT('',(387.213321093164,45.6135081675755,91.591323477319));
#470=CARTESIAN_POINT('',(378.694107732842,207.638743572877,66.6461848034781));
#471=CARTESIAN_POINT('',(433.17831170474,253.396603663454,122.492891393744));
#472=CARTESIAN_POINT('',(500.445116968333,375.,100.));
#473=CARTESIAN_POINT('',(285.091607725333,-375.,100.));
#474=CARTESIAN_POINT('',(309.270321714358,-264.297524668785,86.4064578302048));
#475=CARTESIAN_POINT('',(325.856840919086,-200.08226970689,164.07204721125));
#476=CARTESIAN_POINT('',(247.47112957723,-80.9425320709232,234.992870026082));
#477=CARTESIAN_POINT('',(127.240382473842,2.40271344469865,186.756001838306));
#478=CARTESIAN_POINT('',(115.567806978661,152.518027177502,151.057444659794));
#479=CARTESIAN_POINT('',(191.428893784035,202.025100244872,189.039851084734));
#480=CARTESIAN_POINT('',(285.091607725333,375.,100.));
#481=CARTESIAN_POINT('',(47.4554331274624,-375.,100.));
#482=CARTESIAN_POINT('',(51.0669239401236,-278.639867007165,99.5141662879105));
#483=CARTESIAN_POINT('',(52.9210710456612,-231.452124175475,201.325948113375));
#484=CARTESIAN_POINT('',(3.18149891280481,-90.8615864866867,272.445475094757));
#485=CARTESIAN_POINT('',(-61.0346058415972,45.7948958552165,186.157760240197));
#486=CARTESIAN_POINT('',(-59.6612105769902,205.286893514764,133.941969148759));
#487=CARTESIAN_POINT('',(-11.8049718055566,220.40073671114,189.8209162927));
#488=CARTESIAN_POINT('',(47.4554331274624,375.,100.));
#489=CARTESIAN_POINT('',(-175.903454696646,-375.,100.));
#490=CARTESIAN_POINT('',(-199.823715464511,-320.588060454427,126.731848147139));
#491=CARTESIAN_POINT('',(-216.967937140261,-300.821135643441,242.921959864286));
#492=CARTESIAN_POINT('',(-184.265304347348,-55.1410097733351,206.147478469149));
#493=CARTESIAN_POINT('',(-119.865061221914,249.096629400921,-32.5779079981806));
#494=CARTESIAN_POINT('',(-104.641938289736,431.262460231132,-94.4845569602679));
#495=CARTESIAN_POINT('',(-136.623034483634,348.137040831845,60.785640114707));
#496=CARTESIAN_POINT('',(-175.903454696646,375.,100.));
#497=CARTESIAN_POINT('',(-355.235514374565,-375.,100.));
#498=CARTESIAN_POINT('',(-319.200833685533,-282.590755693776,58.2859511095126));
#499=CARTESIAN_POINT('',(-293.075279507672,-226.888141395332,104.97090627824));
#500=CARTESIAN_POINT('',(-324.119079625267,-68.6572837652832,122.102733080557));
#501=CARTESIAN_POINT('',(-398.972481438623,73.039345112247,53.3701087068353));
#502=CARTESIAN_POINT('',(-423.398679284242,233.384819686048,47.4380317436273));
#503=CARTESIAN_POINT('',(-392.720188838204,253.575952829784,124.952096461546));
#504=CARTESIAN_POINT('',(-355.235514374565,375.,100.));
#505=CARTESIAN_POINT('',(-536.684515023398,-375.,100.));
#506=CARTESIAN_POINT('',(-494.827225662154,-277.129657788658,52.0422385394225));
#507=CARTESIAN_POINT('',(-464.573647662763,-205.017596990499,67.039018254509));
#508=CARTESIAN_POINT('',(-506.334367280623,-72.2467511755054,96.5036749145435));
#509=CARTESIAN_POINT('',(-600.216684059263,9.35641022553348,95.9941925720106));
#510=CARTESIAN_POINT('',(-628.122542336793,166.946160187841,106.349064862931));
#511=CARTESIAN_POINT('',(-587.011939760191,237.095914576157,138.331902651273));
#512=CARTESIAN_POINT('',(-536.684515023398,375.,100.));
#513=CARTESIAN_POINT('',(-644.685568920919,-375.,100.));
#514=CARTESIAN_POINT('',(-644.685568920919,-302.078506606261,100.));
#515=CARTESIAN_POINT('',(-644.685568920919,-237.237234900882,127.59081546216));
#516=CARTESIAN_POINT('',(-644.685568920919,-62.4430976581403,126.406497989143));
#517=CARTESIAN_POINT('',(-644.685568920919,76.6951111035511,77.5962366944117));
#518=CARTESIAN_POINT('',(-644.685568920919,248.895340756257,64.9137717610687));
#519=CARTESIAN_POINT('',(-644.685568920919,298.882075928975,100.));
#520=CARTESIAN_POINT('',(-644.685568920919,375.,100.));
#521=CARTESIAN_POINT('',(-750.,-375.,100.));
#522=CARTESIAN_POINT('',(-750.,-302.078506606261,100.));
#523=CARTESIAN_POINT('',(-750.,-224.483786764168,100.));
#524=CARTESIAN_POINT('',(-750.,-61.5160152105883,100.));
#525=CARTESIAN_POINT('',(-750.,39.4445673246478,100.));
#526=CARTESIAN_POINT('',(-750.,211.849847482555,100.));
#527=CARTESIAN_POINT('',(-750.,298.882075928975,100.));
#528=CARTESIAN_POINT('',(-750.,375.,100.));
#529=B_SPLINE_SURFACE_WITH_KNOTS('',3,3,((#449,#450,#451,#452,#453,#454,#455,#456),(#457,#458,
#459,#460,#461,#462,#463,#464),(#465,#466,#467,#468,#469,#470,#471,#472),(#473,#474,#475,#476,
#477,#478,#479,#480),(#481,#482,#483,#484,#485,#486,#487,#488),(#489,#490,#491,#492,#493,#494,
#495,#496),(#497,#498,#499,#500,#501,#502,#503,#504),(#505,#506,#507,#508,#509,#510,#511,#512),
(#513,#514,#515,#516,#517,#518,#519,#520),(#521,#522,#523,#524,#525,#526,#527,#528)),
.UNSPECIFIED.,.F.,.F.,.F.,(4,1,1,1,1,1,1,4),(4,1,1,1,1,4),(0.,0.161829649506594,
0.33728011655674,0.430707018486,0.637101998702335,0.783997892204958,0.789371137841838,1.),(0.,
0.291685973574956,0.310378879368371,0.65187108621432,0.695528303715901,1.),.UNSPECIFIED.);
#530=CARTESIAN_POINT('',(-200.,-375.,100.));
#531=CARTESIAN_POINT('',(-200.,-373.976783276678,100.013249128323));
#532=CARTESIAN_POINT('',(-200.,-372.953775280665,100.043686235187));
#533=CARTESIAN_POINT('',(-200.,-370.909986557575,100.139214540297));
#534=CARTESIAN_POINT('',(-200.,-369.889204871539,100.204285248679));
#535=CARTESIAN_POINT('',(-200.,-367.850911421,100.369337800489));
#536=CARTESIAN_POINT('',(-200.,-366.833398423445,100.469304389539));
#537=CARTESIAN_POINT('',(-200.,-364.802674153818,100.704142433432));
#538=CARTESIAN_POINT('',(-200.,-363.789461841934,100.839004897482));
#539=CARTESIAN_POINT('',(-200.,-361.768345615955,101.143431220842));
#540=CARTESIAN_POINT('',(-200.,-360.760441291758,101.312992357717));
#541=CARTESIAN_POINT('',(-200.,-358.772955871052,101.682295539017));
#542=CARTESIAN_POINT('',(-200.,-357.793237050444,101.881297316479));
#543=CARTESIAN_POINT('',(-200.,-355.840824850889,102.311462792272));
#544=CARTESIAN_POINT('',(-200.,-354.86813192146,102.542628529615));
#545=CARTESIAN_POINT('',(-200.,-352.93065224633,103.036303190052));
#546=CARTESIAN_POINT('',(-200.,-351.9658661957,103.29881483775));
#547=CARTESIAN_POINT('',(-200.,-350.045017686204,103.854175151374));
#548=CARTESIAN_POINT('',(-200.,-349.088955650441,104.147025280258));
#549=CARTESIAN_POINT('',(-200.,-347.186355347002,104.761850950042));
#550=CARTESIAN_POINT('',(-200.,-346.23981639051,105.083824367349));
#551=CARTESIAN_POINT('',(-200.,-343.567975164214,106.037045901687));
#552=CARTESIAN_POINT('',(-200.,-341.854409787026,106.701465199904));
#553=CARTESIAN_POINT('',(-200.,-338.462458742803,108.11587537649));
#554=CARTESIAN_POINT('',(-200.,-336.78408676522,108.865898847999));
#555=CARTESIAN_POINT('',(-200.,-333.462677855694,110.442325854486));
#556=CARTESIAN_POINT('',(-200.,-331.819659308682,111.26876800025));
#557=CARTESIAN_POINT('',(-200.,-328.568969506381,112.988187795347));
#558=CARTESIAN_POINT('',(-200.,-326.961298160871,113.88116527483));
#559=CARTESIAN_POINT('',(-200.,-323.758782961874,115.736291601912));
#560=CARTESIAN_POINT('',(-200.,-322.164370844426,116.699183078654));
#561=CARTESIAN_POINT('',(-200.,-319.007395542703,118.67427164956));
#562=CARTESIAN_POINT('',(-200.,-317.444819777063,119.68644870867));
#563=CARTESIAN_POINT('',(-200.,-314.347496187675,121.751875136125));
#564=CARTESIAN_POINT('',(-200.,-312.812744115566,122.805118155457));
#565=CARTESIAN_POINT('',(-200.,-309.767251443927,124.944750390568));
#566=CARTESIAN_POINT('',(-200.,-308.256504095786,126.031130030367));
#567=CARTESIAN_POINT('',(-200.,-305.5277843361,128.029898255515));
#568=CARTESIAN_POINT('',(-200.,-304.306610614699,128.93793203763));
#569=CARTESIAN_POINT('',(-200.,-301.874788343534,130.76800087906));
#570=CARTESIAN_POINT('',(-200.,-300.664139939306,131.690036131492));
#571=CARTESIAN_POINT('',(-200.,-298.251192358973,133.544536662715));
#572=CARTESIAN_POINT('',(-200.,-297.048891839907,134.477000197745));
#573=CARTESIAN_POINT('',(-200.,-294.650045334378,136.349307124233));
#574=CARTESIAN_POINT('',(-200.,-293.453499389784,137.289150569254));
#575=CARTESIAN_POINT('',(-200.,-289.867968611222,140.115891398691));
#576=CARTESIAN_POINT('',(-200.,-287.484079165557,142.009231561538));
#577=CARTESIAN_POINT('',(-200.,-282.709664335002,145.791281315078));
#578=CARTESIAN_POINT('',(-200.,-280.31913528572,147.679986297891));
#579=CARTESIAN_POINT('',(-200.,-275.512978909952,151.431208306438));
#580=CARTESIAN_POINT('',(-200.,-273.097325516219,153.293692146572));
#581=CARTESIAN_POINT('',(-200.,-268.257919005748,156.944899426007));
#582=CARTESIAN_POINT('',(-200.,-265.834645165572,158.734254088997));
#583=CARTESIAN_POINT('',(-200.,-260.936465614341,162.241501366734));
#584=CARTESIAN_POINT('',(-200.,-258.46155710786,163.959390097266));
#585=CARTESIAN_POINT('',(-200.,-253.451068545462,167.299025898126));
#586=CARTESIAN_POINT('',(-200.,-250.915557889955,168.920876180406));
#587=CARTESIAN_POINT('',(-200.,-247.060275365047,171.264298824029));
#588=CARTESIAN_POINT('',(-200.,-245.767312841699,172.030109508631));
#589=CARTESIAN_POINT('',(-200.,-243.16281711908,173.529423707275));
#590=CARTESIAN_POINT('',(-200.,-241.851284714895,174.262928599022));
#591=CARTESIAN_POINT('',(-200.,-239.209660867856,175.694431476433));
#592=CARTESIAN_POINT('',(-200.,-237.87957737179,176.392444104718));
#593=CARTESIAN_POINT('',(-200.,-235.200173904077,177.750404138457));
#594=CARTESIAN_POINT('',(-200.,-233.850854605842,178.410352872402));
#595=CARTESIAN_POINT('',(-200.,-230.628355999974,179.92694310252));
#596=CARTESIAN_POINT('',(-200.,-228.746679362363,180.765639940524));
#597=CARTESIAN_POINT('',(-200.,-224.947475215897,182.360030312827));
#598=CARTESIAN_POINT('',(-200.,-223.029932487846,183.11568763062));
#599=CARTESIAN_POINT('',(-200.,-219.161852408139,184.537847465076));
#600=CARTESIAN_POINT('',(-200.,-217.211312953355,185.204344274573));
#601=CARTESIAN_POINT('',(-200.,-213.28065330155,186.443376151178));
#602=CARTESIAN_POINT('',(-200.,-211.30053423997,187.015914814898));
#603=CARTESIAN_POINT('',(-200.,-207.312788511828,188.064135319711));
#604=CARTESIAN_POINT('',(-200.,-205.305137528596,188.539724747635));
#605=CARTESIAN_POINT('',(-200.,-201.268684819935,189.391396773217));
#606=CARTESIAN_POINT('',(-200.,-199.239881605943,189.767472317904));
#607=CARTESIAN_POINT('',(-200.,-195.166305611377,190.419548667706));
#608=CARTESIAN_POINT('',(-200.,-193.121533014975,190.695550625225));
#609=CARTESIAN_POINT('',(-200.,-189.021368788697,191.148341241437));
#610=CARTESIAN_POINT('',(-200.,-186.965978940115,191.325146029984));
#611=CARTESIAN_POINT('',(-200.,-183.275028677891,191.555233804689));
#612=CARTESIAN_POINT('',(-200.,-181.640556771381,191.626500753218));
#613=CARTESIAN_POINT('',(-200.,-178.370150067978,191.709601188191));
#614=CARTESIAN_POINT('',(-200.,-176.734215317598,191.721436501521));
#615=CARTESIAN_POINT('',(-200.,-173.462869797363,191.687566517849));
#616=CARTESIAN_POINT('',(-200.,-171.827459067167,191.641857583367));
#617=CARTESIAN_POINT('',(-200.,-168.559090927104,191.495085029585));
#618=CARTESIAN_POINT('',(-200.,-166.926133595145,191.394019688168));
#619=CARTESIAN_POINT('',(-200.,-163.664663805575,191.138757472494));
#620=CARTESIAN_POINT('',(-200.,-162.036150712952,190.984568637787));
#621=CARTESIAN_POINT('',(-200.,-158.77866283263,190.627382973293));
#622=CARTESIAN_POINT('',(-200.,-157.149707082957,190.424214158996));
#623=CARTESIAN_POINT('',(-200.,-153.89809196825,189.974044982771));
#624=CARTESIAN_POINT('',(-200.,-152.275431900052,189.727049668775));
#625=CARTESIAN_POINT('',(-200.,-149.036615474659,189.193240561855));
#626=CARTESIAN_POINT('',(-200.,-147.420459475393,188.906424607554));
#627=CARTESIAN_POINT('',(-200.,-144.194933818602,188.296553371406));
#628=CARTESIAN_POINT('',(-200.,-142.585564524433,187.973496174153));
#629=CARTESIAN_POINT('',(-200.,-139.373977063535,187.294343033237));
#630=CARTESIAN_POINT('',(-200.,-137.771758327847,186.938249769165));
#631=CARTESIAN_POINT('',(-200.,-133.822336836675,186.021203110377));
#632=CARTESIAN_POINT('',(-200.,-131.479206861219,185.442675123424));
#633=CARTESIAN_POINT('',(-200.,-126.807871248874,184.227932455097));
#634=CARTESIAN_POINT('',(-200.,-124.479666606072,183.591713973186));
#635=CARTESIAN_POINT('',(-200.,-119.837198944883,182.267910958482));
#636=CARTESIAN_POINT('',(-200.,-117.522940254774,181.58031128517));
#637=CARTESIAN_POINT('',(-200.,-112.908564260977,180.159465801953));
#638=CARTESIAN_POINT('',(-200.,-110.608446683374,179.426220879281));
#639=CARTESIAN_POINT('',(-200.,-106.019016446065,177.917937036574));
#640=CARTESIAN_POINT('',(-200.,-103.729719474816,177.142850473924));
#641=CARTESIAN_POINT('',(-200.,-99.1639666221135,175.555766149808));
#642=CARTESIAN_POINT('',(-200.,-96.8875107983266,174.743768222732));
#643=CARTESIAN_POINT('',(-200.,-92.3442477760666,173.08549965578));
#644=CARTESIAN_POINT('',(-200.,-90.0774542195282,172.239191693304));
#645=CARTESIAN_POINT('',(-200.,-85.5554287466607,170.516278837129));
#646=CARTESIAN_POINT('',(-200.,-83.3001968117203,169.639673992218));
#647=CARTESIAN_POINT('',(-200.,-78.7993301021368,167.858387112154));
#648=CARTESIAN_POINT('',(-200.,-76.5537017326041,166.953688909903));
#649=CARTESIAN_POINT('',(-200.,-72.0727541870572,165.119134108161));
#650=CARTESIAN_POINT('',(-200.,-69.837435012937,164.189277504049));
#651=CARTESIAN_POINT('',(-200.,-65.3770584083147,162.306796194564));
#652=CARTESIAN_POINT('',(-200.,-63.1519985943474,161.354177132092));
#653=CARTESIAN_POINT('',(-200.,-58.7110210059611,159.427879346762));
#654=CARTESIAN_POINT('',(-200.,-56.4951032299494,158.454200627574));
#655=CARTESIAN_POINT('',(-200.,-52.0600029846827,156.48224292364));
#656=CARTESIAN_POINT('',(-200.,-49.840866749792,155.48386000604));
#657=CARTESIAN_POINT('',(-200.,-45.4107543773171,153.469141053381));
#658=CARTESIAN_POINT('',(-200.,-43.1997782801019,152.452804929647));
#659=CARTESIAN_POINT('',(-200.,-36.5830579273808,149.381260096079));
#660=CARTESIAN_POINT('',(-200.,-32.1887485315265,147.301385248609));
#661=CARTESIAN_POINT('',(-200.,-23.4300113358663,143.087381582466));
#662=CARTESIAN_POINT('',(-200.,-19.0655650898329,140.953290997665));
#663=CARTESIAN_POINT('',(-200.,-10.3617905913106,136.638783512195));
#664=CARTESIAN_POINT('',(-200.,-6.02245315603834,134.458385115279));
#665=CARTESIAN_POINT('',(-200.,2.63529302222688,130.058131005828));
#666=CARTESIAN_POINT('',(-200.,6.95370491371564,127.8382814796));
#667=CARTESIAN_POINT('',(-200.,15.5733929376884,123.365171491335));
#668=CARTESIAN_POINT('',(-200.,19.8746683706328,121.111909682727));
#669=CARTESIAN_POINT('',(-200.,28.0918737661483,116.773664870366));
#670=CARTESIAN_POINT('',(-200.,32.009004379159,114.690953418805));
#671=CARTESIAN_POINT('',(-200.,39.8338835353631,110.506317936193));
#672=CARTESIAN_POINT('',(-200.,43.7416302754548,108.404390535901));
#673=CARTESIAN_POINT('',(-200.,51.5496507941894,104.185263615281));
#674=CARTESIAN_POINT('',(-200.,55.4499233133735,102.068061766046));
#675=CARTESIAN_POINT('',(-200.,63.2448516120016,97.8222270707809));
#676=CARTESIAN_POINT('',(-200.,67.1395066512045,95.6935928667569));
#677=CARTESIAN_POINT('',(-200.,74.9250464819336,91.4287179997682));
#678=CARTESIAN_POINT('',(-200.,78.8159309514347,89.2924767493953));
#679=CARTESIAN_POINT('',(-200.,86.5958117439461,85.0162778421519));
#680=CARTESIAN_POINT('',(-200.,90.4848080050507,82.8763200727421));
#681=CARTESIAN_POINT('',(-200.,98.2516813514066,78.6028958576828));
#682=CARTESIAN_POINT('',(-200.,102.129557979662,76.4694285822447));
#683=CARTESIAN_POINT('',(-200.,109.887556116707,72.2070514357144));
#684=CARTESIAN_POINT('',(-200.,113.767677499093,70.0781413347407));
#685=CARTESIAN_POINT('',(-200.,121.532543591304,65.8294916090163));
#686=CARTESIAN_POINT('',(-200.,125.41728791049,63.7097512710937));
#687=CARTESIAN_POINT('',(-200.,133.19407805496,59.4846103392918));
#688=CARTESIAN_POINT('',(-200.,137.086123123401,57.3792083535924));
#689=CARTESIAN_POINT('',(-200.,144.880612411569,53.1886637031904));
#690=CARTESIAN_POINT('',(-200.,148.783055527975,51.1035189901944));
#691=CARTESIAN_POINT('',(-200.,154.647367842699,47.9962582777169));
#692=CARTESIAN_POINT('',(-200.,156.603838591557,46.9639529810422));
#693=CARTESIAN_POINT('',(-200.,160.520896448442,44.9071843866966));
#694=CARTESIAN_POINT('',(-200.,162.481483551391,43.8827210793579));
#695=CARTESIAN_POINT('',(-200.,166.805823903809,41.6357137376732));
#696=CARTESIAN_POINT('',(-200.,169.170622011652,40.4151786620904));
#697=CARTESIAN_POINT('',(-200.,173.908148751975,37.9893514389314));
#698=CARTESIAN_POINT('',(-200.,176.280877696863,36.784059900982));
#699=CARTESIAN_POINT('',(-200.,181.035671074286,34.3913114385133));
#700=CARTESIAN_POINT('',(-200.,183.417736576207,33.2038566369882));
#701=CARTESIAN_POINT('',(-200.,188.192848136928,30.8498499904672));
#702=CARTESIAN_POINT('',(-200.,190.585896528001,29.6833028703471));
#703=CARTESIAN_POINT('',(-200.,195.38492920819,27.3748113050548));
#704=CARTESIAN_POINT('',(-200.,197.790917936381,26.2328760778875));
#705=CARTESIAN_POINT('',(-200.,202.621441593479,23.9766060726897));
#706=CARTESIAN_POINT('',(-200.,205.046003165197,22.8623281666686));
#707=CARTESIAN_POINT('',(-200.,208.695003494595,21.2178128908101));
#708=CARTESIAN_POINT('',(-200.,209.913383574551,20.6741159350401));
#709=CARTESIAN_POINT('',(-200.,212.354505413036,19.596609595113));
#710=CARTESIAN_POINT('',(-200.,213.577247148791,19.0628001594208));
#711=CARTESIAN_POINT('',(-200.,216.027042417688,18.0062520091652));
#712=CARTESIAN_POINT('',(-200.,217.254094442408,17.4835097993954));
#713=CARTESIAN_POINT('',(-200.,219.713271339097,16.4500905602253));
#714=CARTESIAN_POINT('',(-200.,220.945396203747,15.9394135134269));
#715=CARTESIAN_POINT('',(-200.,223.414515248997,14.9317233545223));
#716=CARTESIAN_POINT('',(-200.,224.651506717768,14.4347036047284));
#717=CARTESIAN_POINT('',(-200.,227.131416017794,13.4556320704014));
#718=CARTESIAN_POINT('',(-200.,228.374333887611,12.973580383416));
#719=CARTESIAN_POINT('',(-200.,230.866157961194,12.0264494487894));
#720=CARTESIAN_POINT('',(-200.,232.115062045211,11.5613646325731));
#721=CARTESIAN_POINT('',(-200.,234.619765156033,10.6501929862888));
#722=CARTESIAN_POINT('',(-200.,235.875564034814,10.204105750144));
#723=CARTESIAN_POINT('',(-200.,238.328331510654,9.35645652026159));
#724=CARTESIAN_POINT('',(-200.,239.524916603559,8.95378683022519));
#725=CARTESIAN_POINT('',(-200.,241.925434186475,8.17048330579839));
#726=CARTESIAN_POINT('',(-200.,243.129367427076,7.78985176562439));
#727=CARTESIAN_POINT('',(-200.,245.545336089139,7.05381813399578));
#728=CARTESIAN_POINT('',(-200.,246.757373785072,6.69842348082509));
#729=CARTESIAN_POINT('',(-200.,249.190517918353,6.01677625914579));
#730=CARTESIAN_POINT('',(-200.,250.411629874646,5.69054332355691));
#731=CARTESIAN_POINT('',(-200.,252.857305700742,5.07381978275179));
#732=CARTESIAN_POINT('',(-200.,254.081831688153,4.78318043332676));
#733=CARTESIAN_POINT('',(-200.,255.92523034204,4.37757291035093));
#734=CARTESIAN_POINT('',(-200.,256.540781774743,4.24743203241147));
#735=CARTESIAN_POINT('',(-200.,257.774117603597,3.99822935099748));
#736=CARTESIAN_POINT('',(-200.,258.391901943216,3.87916726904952));
#737=CARTESIAN_POINT('',(-200.,259.629221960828,3.65328001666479));
#738=CARTESIAN_POINT('',(-200.,260.24875593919,3.54644556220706));
#739=CARTESIAN_POINT('',(-200.,261.489967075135,3.34614449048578));
#740=CARTESIAN_POINT('',(-200.,262.111644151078,3.25267736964));
#741=CARTESIAN_POINT('',(-200.,263.356681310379,3.08057119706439));
#742=CARTESIAN_POINT('',(-200.,263.980040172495,3.00192335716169));
#743=CARTESIAN_POINT('',(-200.,265.228612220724,2.8610114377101));
#744=CARTESIAN_POINT('',(-200.,265.85382536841,2.79874702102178));
#745=CARTESIAN_POINT('',(-200.,267.018726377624,2.69987902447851));
#746=CARTESIAN_POINT('',(-200.,267.558212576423,2.66091066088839));
#747=CARTESIAN_POINT('',(-200.,268.638061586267,2.59787642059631));
#748=CARTESIAN_POINT('',(-200.,269.178424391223,2.57381044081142));
#749=CARTESIAN_POINT('',(-200.,270.259646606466,2.54160268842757));
#750=CARTESIAN_POINT('',(-200.,270.80050602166,2.53346107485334));
#751=CARTESIAN_POINT('',(-200.,271.882197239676,2.53418911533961));
#752=CARTESIAN_POINT('',(-200.,272.423029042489,2.54305877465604));
#753=CARTESIAN_POINT('',(-200.,274.044214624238,2.59685148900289));
#754=CARTESIAN_POINT('',(-200.,275.123844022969,2.66893847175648));
#755=CARTESIAN_POINT('',(-200.,277.274846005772,2.8948086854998));
#756=CARTESIAN_POINT('',(-200.,278.3462182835,3.04859493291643));
#757=CARTESIAN_POINT('',(-200.,280.128616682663,3.38213084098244));
#758=CARTESIAN_POINT('',(-200.,280.844250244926,3.53744649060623));
#759=CARTESIAN_POINT('',(-200.,282.264744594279,3.89164026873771));
#760=CARTESIAN_POINT('',(-200.,282.969605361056,4.09051847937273));
#761=CARTESIAN_POINT('',(-200.,284.36499283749,4.53340542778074));
#762=CARTESIAN_POINT('',(-200.,285.055520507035,4.77741113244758));
#763=CARTESIAN_POINT('',(-200.,286.417559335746,5.31086556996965));
#764=CARTESIAN_POINT('',(-200.,287.089099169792,5.60024092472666));
#765=CARTESIAN_POINT('',(-200.,288.410791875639,6.22444853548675));
#766=CARTESIAN_POINT('',(-200.,289.060942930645,6.55928464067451));
#767=CARTESIAN_POINT('',(-200.,290.336445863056,7.27296359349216));
#768=CARTESIAN_POINT('',(-200.,290.961803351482,7.65179640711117));
#769=CARTESIAN_POINT('',(-200.,292.097548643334,8.39382963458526));
#770=CARTESIAN_POINT('',(-200.,292.611569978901,8.75149091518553));
#771=CARTESIAN_POINT('',(-200.,293.618421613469,9.49540110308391));
#772=CARTESIAN_POINT('',(-200.,294.111253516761,9.88164784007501));
#773=CARTESIAN_POINT('',(-200.,295.075023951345,10.6804407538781));
#774=CARTESIAN_POINT('',(-200.,295.545963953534,11.0929851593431));
#775=CARTESIAN_POINT('',(-200.,296.466241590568,11.9423759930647));
#776=CARTESIAN_POINT('',(-200.,296.915556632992,12.3792468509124));
#777=CARTESIAN_POINT('',(-200.,297.792295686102,13.2744048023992));
#778=CARTESIAN_POINT('',(-200.,298.219719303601,13.7326922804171));
#779=CARTESIAN_POINT('',(-200.,299.053232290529,14.6681905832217));
#780=CARTESIAN_POINT('',(-200.,299.459322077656,15.1454010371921));
#781=CARTESIAN_POINT('',(-200.,300.500356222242,16.4221992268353));
#782=CARTESIAN_POINT('',(-200.,301.118417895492,17.2355941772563));
#783=CARTESIAN_POINT('',(-200.,302.305595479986,18.8981042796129));
#784=CARTESIAN_POINT('',(-200.,302.874668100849,19.7472500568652));
#785=CARTESIAN_POINT('',(-200.,303.969656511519,21.4741133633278));
#786=CARTESIAN_POINT('',(-200.,304.495523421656,22.3518617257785));
#787=CARTESIAN_POINT('',(-200.,305.509320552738,24.1289781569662));
#788=CARTESIAN_POINT('',(-200.,305.99724714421,25.0283482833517));
#789=CARTESIAN_POINT('',(-200.,306.943550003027,26.8489330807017));
#790=CARTESIAN_POINT('',(-200.,307.401741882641,27.7702430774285));
#791=CARTESIAN_POINT('',(-200.,308.290642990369,29.6249775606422));
#792=CARTESIAN_POINT('',(-200.,308.721375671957,30.5583908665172));
#793=CARTESIAN_POINT('',(-200.,309.560792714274,32.4347363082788));
#794=CARTESIAN_POINT('',(-200.,309.969482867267,33.3776658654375));
#795=CARTESIAN_POINT('',(-200.,310.76963267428,35.270716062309));
#796=CARTESIAN_POINT('',(-200.,311.161093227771,36.2208363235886));
#797=CARTESIAN_POINT('',(-200.,312.107904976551,38.5634215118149));
#798=CARTESIAN_POINT('',(-200.,312.656029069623,39.9587952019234));
#799=CARTESIAN_POINT('',(-200.,313.737566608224,42.7553088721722));
#800=CARTESIAN_POINT('',(-200.,314.270978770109,44.1564493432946));
#801=CARTESIAN_POINT('',(-200.,315.334641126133,46.9600971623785));
#802=CARTESIAN_POINT('',(-200.,315.864890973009,48.3626046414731));
#803=CARTESIAN_POINT('',(-200.,316.933053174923,51.1644337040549));
#804=CARTESIAN_POINT('',(-200.,317.470964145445,52.5637558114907));
#805=CARTESIAN_POINT('',(-200.,318.565213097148,55.3550827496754));
#806=CARTESIAN_POINT('',(-200.,319.121549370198,56.7470882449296));
#807=CARTESIAN_POINT('',(-200.,320.263466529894,59.5192288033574));
#808=CARTESIAN_POINT('',(-200.,320.849048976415,60.8993632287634));
#809=CARTESIAN_POINT('',(-200.,322.071947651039,63.6682234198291));
#810=CARTESIAN_POINT('',(-200.,322.710038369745,65.0566097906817));
#811=CARTESIAN_POINT('',(-200.,324.039863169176,67.8077606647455));
#812=CARTESIAN_POINT('',(-200.,324.73160002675,69.1705238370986));
#813=CARTESIAN_POINT('',(-200.,326.181103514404,71.8616538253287));
#814=CARTESIAN_POINT('',(-200.,326.938905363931,73.1900017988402));
#815=CARTESIAN_POINT('',(-200.,328.527474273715,75.7922049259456));
#816=CARTESIAN_POINT('',(-200.,329.357786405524,77.0663344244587));
#817=CARTESIAN_POINT('',(-200.,330.668169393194,78.9315197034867));
#818=CARTESIAN_POINT('',(-200.,331.115737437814,79.545524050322));
#819=CARTESIAN_POINT('',(-200.,332.033615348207,80.7562583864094));
#820=CARTESIAN_POINT('',(-200.,332.503922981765,81.352990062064));
#821=CARTESIAN_POINT('',(-200.,333.467712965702,82.5265163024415));
#822=CARTESIAN_POINT('',(-200.,333.96117286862,83.1033292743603));
#823=CARTESIAN_POINT('',(-200.,334.972216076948,84.2353293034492));
#824=CARTESIAN_POINT('',(-200.,335.489796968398,84.7905185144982));
#825=CARTESIAN_POINT('',(-200.,336.642531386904,85.9725608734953));
#826=CARTESIAN_POINT('',(-200.,337.282365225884,86.5948679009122));
#827=CARTESIAN_POINT('',(-200.,338.595636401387,87.8029561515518));
#828=CARTESIAN_POINT('',(-200.,339.269072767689,88.3887384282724));
#829=CARTESIAN_POINT('',(-200.,340.648586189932,89.520459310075));
#830=CARTESIAN_POINT('',(-200.,341.354660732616,90.0664009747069));
#831=CARTESIAN_POINT('',(-200.,342.797656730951,91.1155336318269));
#832=CARTESIAN_POINT('',(-200.,343.534570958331,91.6187345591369));
#833=CARTESIAN_POINT('',(-200.,345.037120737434,92.5803865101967));
#834=CARTESIAN_POINT('',(-200.,345.80275863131,93.038833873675));
#835=CARTESIAN_POINT('',(-200.,347.359827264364,93.9095106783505));
#836=CARTESIAN_POINT('',(-200.,348.151256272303,94.3217432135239));
#837=CARTESIAN_POINT('',(-200.,349.553591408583,95.0010508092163));
#838=CARTESIAN_POINT('',(-200.,350.159519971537,95.2784666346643));
#839=CARTESIAN_POINT('',(-200.,351.38267199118,95.8073035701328));
#840=CARTESIAN_POINT('',(-200.,351.999896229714,96.0587228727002));
#841=CARTESIAN_POINT('',(-200.,353.244183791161,96.5358097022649));
#842=CARTESIAN_POINT('',(-200.,353.871246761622,96.7614781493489));
#843=CARTESIAN_POINT('',(-200.,355.133910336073,97.1875813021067));
#844=CARTESIAN_POINT('',(-200.,355.76951173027,97.3880136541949));
#845=CARTESIAN_POINT('',(-200.,357.690478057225,97.9533634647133));
#846=CARTESIAN_POINT('',(-200.,358.986919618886,98.2811610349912));
#847=CARTESIAN_POINT('',(-200.,361.59924632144,98.8444958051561));
#848=CARTESIAN_POINT('',(-200.,362.91512977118,99.0800409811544));
#849=CARTESIAN_POINT('',(-200.,365.130543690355,99.4042484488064));
#850=CARTESIAN_POINT('',(-200.,366.026825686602,99.5157740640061));
#851=CARTESIAN_POINT('',(-200.,367.823035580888,99.7028961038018));
#852=CARTESIAN_POINT('',(-200.,368.722963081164,99.7784963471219));
#853=CARTESIAN_POINT('',(-200.,370.518695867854,99.895879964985));
#854=CARTESIAN_POINT('',(-200.,371.414486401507,99.9378944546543));
#855=CARTESIAN_POINT('',(-200.,373.206893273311,99.9913139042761));
#856=CARTESIAN_POINT('',(-200.,374.103509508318,100.002722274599));
#857=CARTESIAN_POINT('',(-200.,375.,100.));
#858=B_SPLINE_CURVE_WITH_KNOTS('',3,(#530,#531,#532,#533,#534,#535,#536,#537,#538,#539,#540,
#541,#542,#543,#544,#545,#546,#547,#548,#549,#550,#551,#552,#553,#554,#555,#556,#557,#558,#559,
#560,#561,#562,#563,#564,#565,#566,#567,#568,#569,#570,#571,#572,#573,#574,#575,#576,#577,#578,
#579,#580,#581,#582,#583,#584,#585,#586,#587,#588,#589,#590,#591,#592,#593,#594,#595,#596,#597,
#598,#599,#600,#601,#602,#603,#604,#605,#606,#607,#608,#609,#610,#611,#612,#613,#614,#615,#616,
#617,#618,#619,#620,#621,#622,#623,#624,#625,#626,#627,#628,#629,#630,#631,#632,#633,#634,#635,
#636,#637,#638,#639,#640,#641,#642,#643,#644,#645,#646,#647,#648,#649,#650,#651,#652,#653,#654,
#655,#656,#657,#658,#659,#660,#661,#662,#663,#664,#665,#666,#667,#668,#669,#670,#671,#672,#673,
#674,#675,#676,#677,#678,#679,#680,#681,#682,#683,#684,#685,#686,#687,#688,#689,#690,#691,#692,
#693,#694,#695,#696,#697,#698,#699,#700,#701,#702,#703,#704,#705,#706,#707,#708,#709,#710,#711,
#712,#713,#714,#715,#716,#717,#718,#719,#720,#721,#722,#723,#724,#725,#726,#727,#728,#729,#730,
#731,#732,#733,#734,#735,#736,#737,#738,#739,#740,#741,#742,#743,#744,#745,#746,#747,#748,#749,
#750,#751,#752,#753,#754,#755,#756,#757,#758,#759,#760,#761,#762,#763,#764,#765,#766,#767,#768,
#769,#770,#771,#772,#773,#774,#775,#776,#777,#778,#779,#780,#781,#782,#783,#784,#785,#786,#787,
#788,#789,#790,#791,#792,#793,#794,#795,#796,#797,#798,#799,#800,#801,#802,#803,#804,#805,#806,
#807,#808,#809,#810,#811,#812,#813,#814,#815,#816,#817,#818,#819,#820,#821,#822,#823,#824,#825,
#826,#827,#828,#829,#830,#831,#832,#833,#834,#835,#836,#837,#838,#839,#840,#841,#842,#843,#844,
#845,#846,#847,#848,#849,#850,#851,#852,#853,#854,#855,#856,#857),.UNSPECIFIED.,.F.,.F.,(4,2,2,
2,2,2,2,2,2,2,2,2,2,2,2,2,2,2,2,2,2,2,2,2,2,2,2,2,2,2,2,2,2,2,2,2,2,2,2,2,2,2,2,2,2,2,2,2,2,2,2,
2,2,2,2,2,2,2,2,2,2,2,2,2,2,2,2,2,2,2,2,2,2,2,2,2,2,2,2,2,2,2,2,2,2,2,2,2,2,2,2,2,2,2,2,2,2,2,2,
2,2,2,2,2,2,2,2,2,2,2,2,2,2,2,2,2,2,2,2,2,2,2,2,2,2,2,2,2,2,2,2,2,2,2,2,2,2,2,2,2,2,2,2,2,2,2,2,
2,2,2,2,2,2,2,2,2,2,2,2,2,2,2,2,4),(0.,3.06978401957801,6.13775391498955,9.20438435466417,
12.2702254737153,15.335826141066,18.3344547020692,21.3332734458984,24.3323530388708,
27.3315773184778,30.3305830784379,35.8414153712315,41.3543529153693,46.8700912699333,
52.3858155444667,57.9725634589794,63.5570589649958,69.1406944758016,74.7227314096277,
79.2879325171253,83.8531966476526,88.4177084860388,92.982253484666,102.115097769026,
111.254876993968,120.405337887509,129.441339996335,138.477832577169,147.504430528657,
152.012256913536,156.51989087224,161.025649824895,165.531251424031,171.709686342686,
177.890805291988,184.072319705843,190.253597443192,196.440739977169,202.628320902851,
208.815830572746,215.002333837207,219.909354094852,224.816223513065,229.723403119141,
234.630735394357,239.537325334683,244.461401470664,249.384910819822,254.308687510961,
259.232724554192,264.156362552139,271.395953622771,278.636021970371,285.878232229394,
293.120301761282,300.370798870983,307.621328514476,314.879968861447,322.138597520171,
329.40148372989,336.664371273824,343.925476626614,351.186580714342,358.486629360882,
365.786714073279,380.371205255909,394.945682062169,409.514440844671,424.080934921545,
438.648017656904,451.957141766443,465.26864599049,478.582224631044,491.897421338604,
505.213669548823,518.530328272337,531.808373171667,545.08573170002,558.362038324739,
571.637037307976,584.910679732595,591.546996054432,598.18330419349,606.166851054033,
614.150716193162,622.135524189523,630.122114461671,638.111645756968,646.116434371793,
650.118961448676,654.121467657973,658.122690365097,662.123907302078,666.123143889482,
670.122406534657,674.120344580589,678.118197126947,681.905572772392,685.693341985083,
689.482223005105,693.273635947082,697.048620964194,698.936013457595,700.823358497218,
702.709260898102,704.595092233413,706.479801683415,708.364472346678,709.986961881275,
711.609440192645,713.231934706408,714.85442972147,718.09766576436,721.341021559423,
723.536683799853,725.732350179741,727.927869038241,730.119872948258,732.312062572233,
734.50375321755,736.381375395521,738.258855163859,740.136208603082,742.015482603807,
743.894790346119,745.774061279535,748.836501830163,751.901621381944,754.970162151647,
758.038996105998,761.125330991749,764.208993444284,767.291841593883,770.374528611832,
774.871847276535,779.36955710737,783.867752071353,788.365144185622,792.862120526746,
797.359336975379,801.942450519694,806.525801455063,811.111610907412,815.670473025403,
817.949472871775,820.228249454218,822.50486053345,824.781244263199,827.45756115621,
830.133800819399,832.809834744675,835.485244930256,838.16087374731,840.836323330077,
842.834990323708,844.83379618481,846.832530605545,848.83145129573,852.839167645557,
856.846537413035,859.555421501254,862.264017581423,864.953810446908,867.643303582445),.UNSPECIFIED.);
#859=CARTESIAN_POINT('',(-200.,-375.,100.));
#860=VERTEX_POINT('',#859);
#861=CARTESIAN_POINT('',(-200.,375.,100.));
#862=VERTEX_POINT('',#861);
#863=EDGE_CURVE('E11',#860,#862,#858,.T.);
#864=CARTESIAN_POINT('',(-750.,-375.,100.));
#865=CARTESIAN_POINT('',(-644.685568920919,-375.,100.));
#866=CARTESIAN_POINT('',(-536.684515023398,-375.,100.));
#867=CARTESIAN_POINT('',(-355.235514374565,-375.,100.));
#868=CARTESIAN_POINT('',(-175.903454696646,-375.,100.));
#869=CARTESIAN_POINT('',(47.4554331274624,-375.,100.));
#870=CARTESIAN_POINT('',(285.091607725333,-375.,100.));
#871=CARTESIAN_POINT('',(500.445116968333,-375.,100.));
#872=CARTESIAN_POINT('',(669.085175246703,-375.,100.));
#873=CARTESIAN_POINT('',(750.,-375.,100.));
#874=B_SPLINE_CURVE_WITH_KNOTS('',3,(#864,#865,#866,#867,#868,#869,#870,#871,#872,#873),
.UNSPECIFIED.,.F.,.F.,(4,1,1,1,1,1,1,4),(0.,0.210628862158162,0.216002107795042,
0.362898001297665,0.569292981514,0.66271988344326,0.838170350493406,1.),.UNSPECIFIED.);
#875=EDGE_CURVE('E97',#860,#390,#874,.T.);
#876=CARTESIAN_POINT('',(750.,375.,100.));
#877=CARTESIAN_POINT('',(669.085175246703,375.,100.));
#878=CARTESIAN_POINT('',(500.445116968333,375.,100.));
#879=CARTESIAN_POINT('',(285.091607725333,375.,100.));
#880=CARTESIAN_POINT('',(47.4554331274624,375.,100.));
#881=CARTESIAN_POINT('',(-175.903454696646,375.,100.));
#882=CARTESIAN_POINT('',(-355.235514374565,375.,100.));
#883=CARTESIAN_POINT('',(-536.684515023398,375.,100.));
#884=CARTESIAN_POINT('',(-644.685568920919,375.,100.));
#885=CARTESIAN_POINT('',(-750.,375.,100.));
#886=B_SPLINE_CURVE_WITH_KNOTS('',3,(#876,#877,#878,#879,#880,#881,#882,#883,#884,#885),
.UNSPECIFIED.,.F.,.F.,(4,1,1,1,1,1,1,4),(0.,0.161829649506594,0.33728011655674,0.430707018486,
0.637101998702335,0.783997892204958,0.789371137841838,1.),.UNSPECIFIED.);
#887=EDGE_CURVE('E94',#388,#862,#886,.T.);
#888=ORIENTED_EDGE('',*,*,#863,.F.);
#889=ORIENTED_EDGE('',*,*,#875,.T.);
#890=ORIENTED_EDGE('',*,*,#391,.F.);
#891=ORIENTED_EDGE('',*,*,#887,.T.);
#892=EDGE_LOOP('',(#888,#889,#890,#891));
#893=FACE_BOUND('',#892,.T.);
#894=ADVANCED_FACE('F110',(#893),#529,.F.);
#895=CARTESIAN_POINT('',(-750.,375.,253.111113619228));
#896=DIRECTION('',(0.,-1.,0.));
#897=DIRECTION('',(0.,0.,-1.));
#898=AXIS2_PLACEMENT_3D('',#895,#896,#897);
#899=PLANE('',#898);
#900=DIRECTION('',(0.,0.,-1.));
#901=VECTOR('',#900,1.);
#902=CARTESIAN_POINT('',(-200.,375.,253.120113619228));
#903=LINE('',#902,#901);
#904=EDGE_CURVE('E154',#862,#436,#903,.T.);
#905=ORIENTED_EDGE('',*,*,#904,.F.);
#906=ORIENTED_EDGE('',*,*,#887,.F.);
#907=ORIENTED_EDGE('',*,*,#413,.T.);
#908=ORIENTED_EDGE('',*,*,#443,.T.);
#909=EDGE_LOOP('',(#905,#906,#907,#908));
#910=FACE_BOUND('',#909,.T.);
#911=ADVANCED_FACE('F121',(#910),#899,.F.);
#912=CARTESIAN_POINT('',(-750.,-375.,253.111113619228));
#913=DIRECTION('',(0.,1.,0.));
#914=DIRECTION('',(0.,0.,1.));
#915=AXIS2_PLACEMENT_3D('',#912,#913,#914);
#916=PLANE('',#915);
#917=DIRECTION('',(0.,0.,-1.));
#918=VECTOR('',#917,1.);
#919=CARTESIAN_POINT('',(-200.,-375.,253.120113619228));
#920=LINE('',#919,#918);
#921=EDGE_CURVE('E56',#860,#428,#920,.T.);
#922=ORIENTED_EDGE('',*,*,#921,.T.);
#923=ORIENTED_EDGE('',*,*,#429,.T.);
#924=ORIENTED_EDGE('',*,*,#399,.F.);
#925=ORIENTED_EDGE('',*,*,#875,.F.);
#926=EDGE_LOOP('',(#922,#923,#924,#925));
#927=FACE_BOUND('',#926,.T.);
#928=ADVANCED_FACE('F37',(#927),#916,.F.);
#929=CARTESIAN_POINT('',(-200.,375.,253.120113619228));
#930=DIRECTION('',(-1.,0.,0.));
#931=DIRECTION('',(0.,-1.,0.));
#932=AXIS2_PLACEMENT_3D('',#929,#930,#931);
#933=PLANE('',#932);
#934=ORIENTED_EDGE('',*,*,#863,.T.);
#935=ORIENTED_EDGE('',*,*,#904,.T.);
#936=ORIENTED_EDGE('',*,*,#437,.F.);
#937=ORIENTED_EDGE('',*,*,#921,.F.);
#938=EDGE_LOOP('',(#934,#935,#936,#937));
#939=FACE_BOUND('',#938,.T.);
#940=ADVANCED_FACE('F145',(#939),#933,.T.);
#941=CLOSED_SHELL('',(#417,#448,#894,#911,#928,#940));
#942=MANIFOLD_SOLID_BREP('B2',#941);
#943=ADVANCED_BREP_SHAPE_REPRESENTATION('',(#18,#942),#14);
#944=SHAPE_DEFINITION_REPRESENTATION(#9,#943);
ENDSEC;
END-ISO-10303-21;
